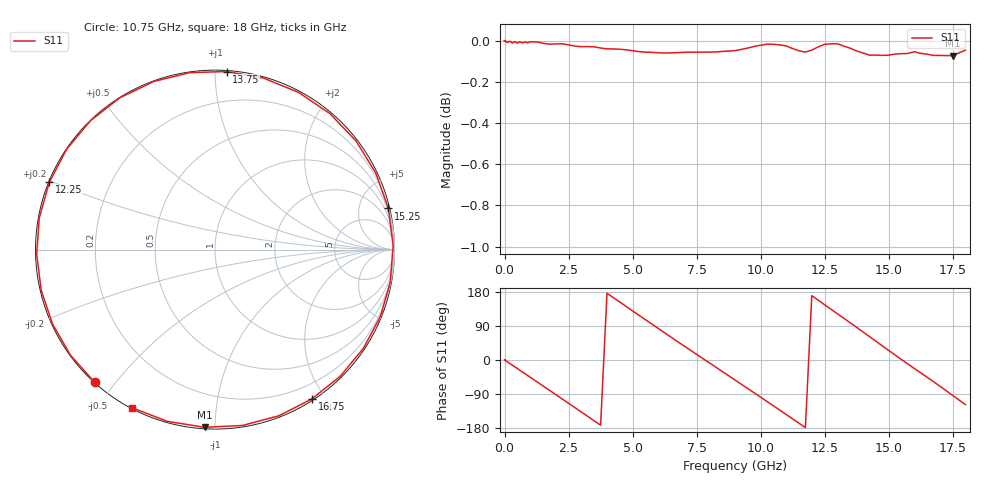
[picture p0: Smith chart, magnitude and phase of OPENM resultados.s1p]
#	HZ	S	MA	R	50.00
! Rohde & Schwarz Vector Network Analyzer
! Rohde-Schwarz,ZNB43-2Port,1334333092101683,4.21
! Created: UTC 09/15/2026, 11:47:42 AM
! freq[Hz]	mag:S12	ang:S12
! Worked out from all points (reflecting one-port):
!   116 points, 9 kHz to 18 GHz, reference 50 ohm
!   lowest |S11| = -0.1 dB at 17.5 GHz (marker M1), VSWR 240.64, Z = 0.393 - j47.2 ohm
!   phase of S11 starts at 0 deg and turns -838 deg over the sweep
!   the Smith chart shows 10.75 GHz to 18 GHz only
!   S11 on the Smith chart (normalised r, x): 10.75 GHz: 0.00, -0.44; 12.25 GHz: 0.00, +0.20; 13.75 GHz: 0.01, +1.07; 15.25 GHz: 0.27, +8.54; 16.75 GHz: 0.02, -1.84; 18 GHz: 0.00, -0.60
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9000  1 0.0
7e8  0.9988 -31.8
1.5e9  0.9986 -68.4
2e9  0.9983 -91.3
2.5e9  0.9977 -114.3
3.25e9  0.9968 -148.9
3.75e9  0.996 -172.1
4.25e9  0.9955 164.5
4.75e9  0.995 141.2
5.75e9  0.9936 94.9
6.25e9  0.9932 71.8
7e9  0.9936 37.6
7.5e9  0.9937 14.8
8e9  0.9937 -7.7
8.5e9  0.9941 -30.1
9.25e9  0.9952 -64.1
1e10  0.9975 -98.0
1.075e10  0.9977 -132.2
1.15e10  0.9944 -166.8
1.225e10  0.9966 157.9
1.3e10  0.9983 122.1
1.375e10  0.9943 86.3
1.45e10  0.992 49.8
1.525e10  0.9926 13.3
1.6e10  0.9939 -22.1
1.675e10  0.9919 -57.0
1.75e10  0.9917 -93.3
1.8e10  0.9948 -117.7
